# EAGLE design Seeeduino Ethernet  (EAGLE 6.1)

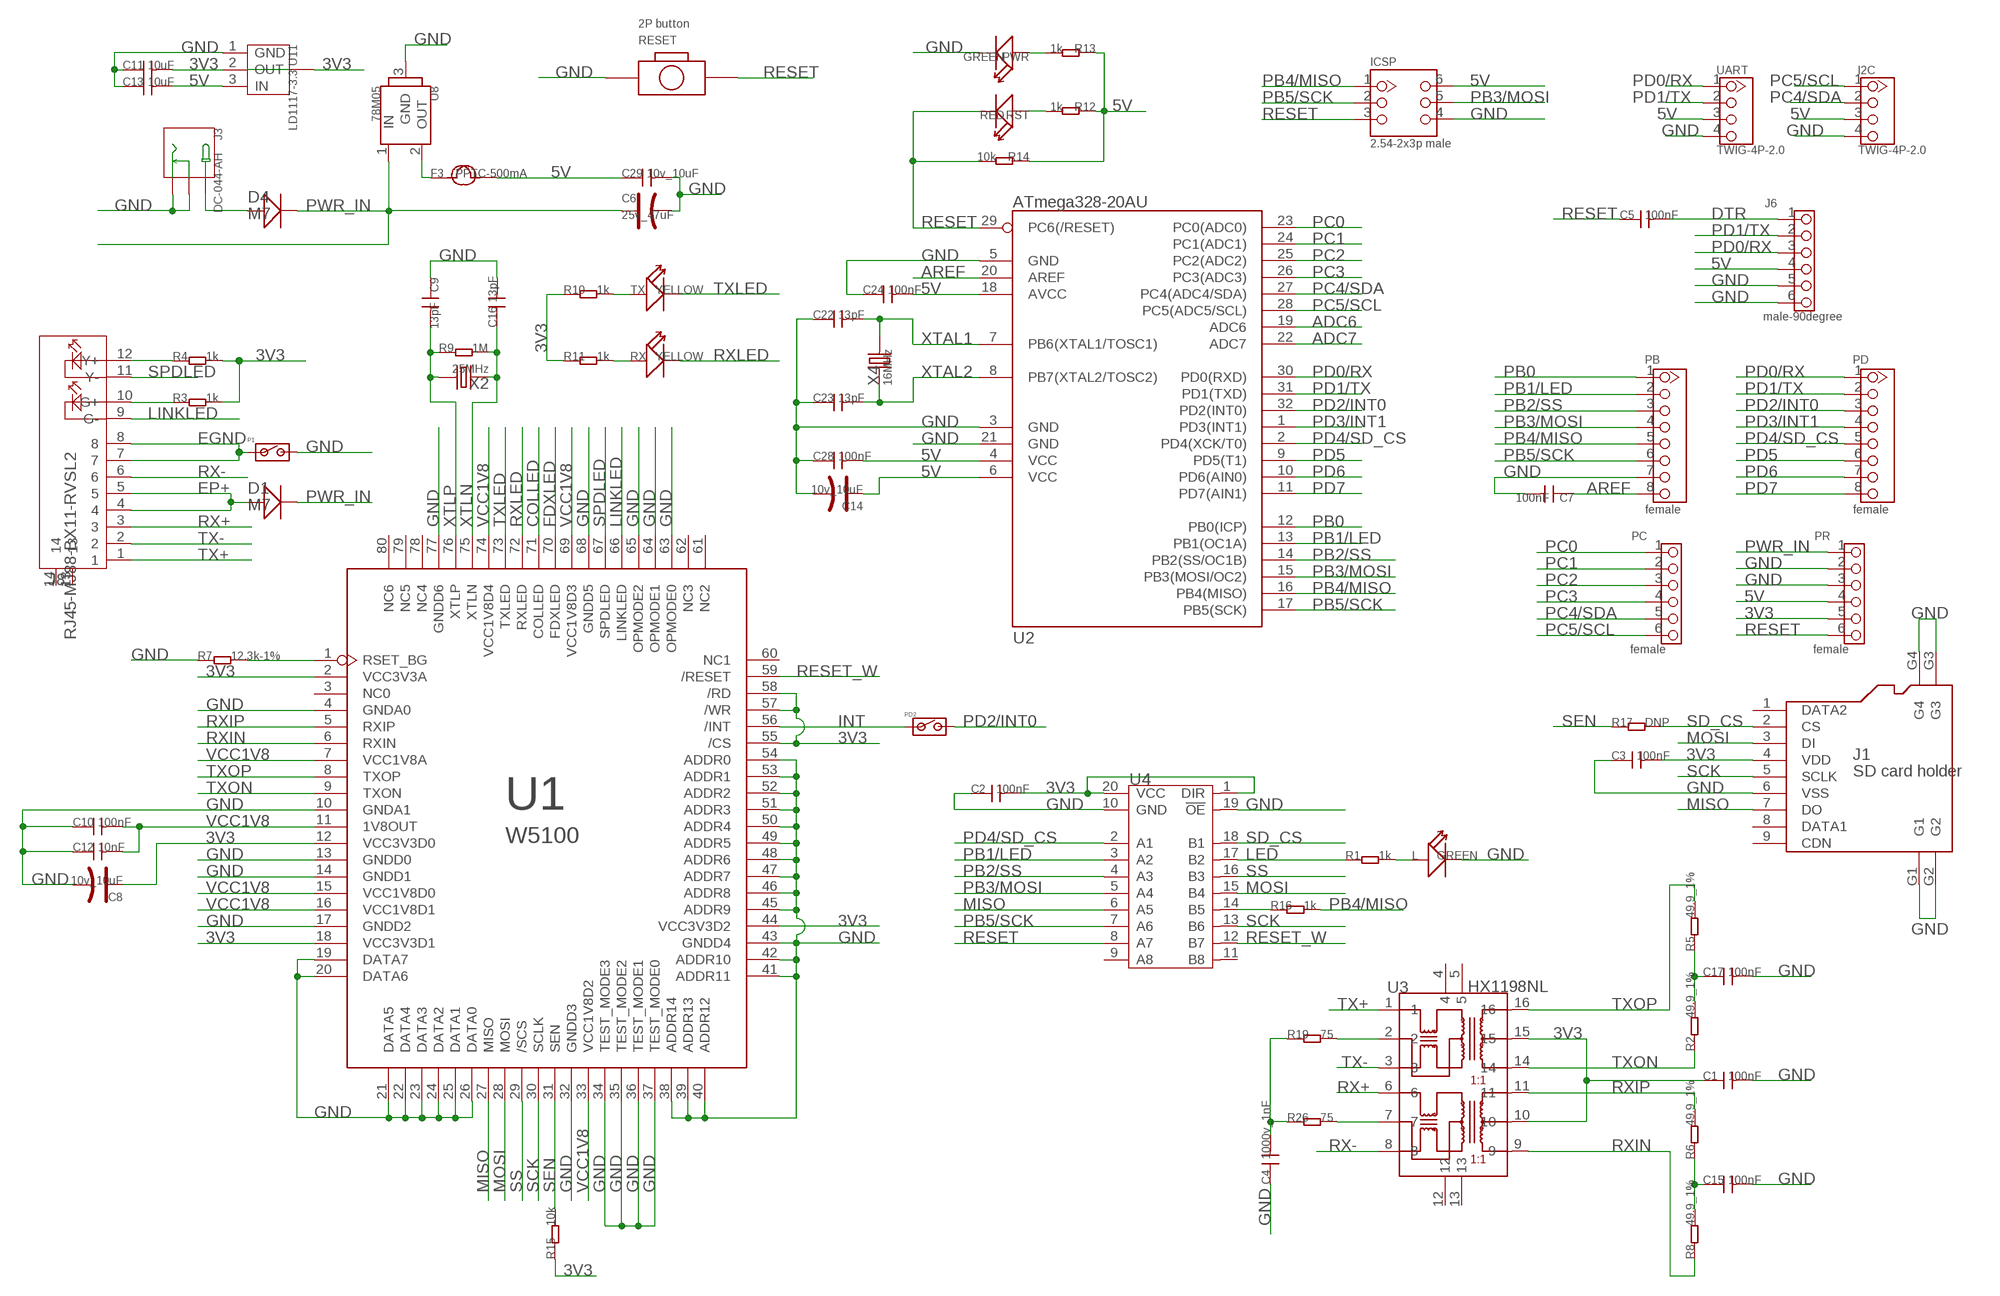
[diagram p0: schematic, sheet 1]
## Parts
C1  100nF  C-0603  [0603]
C2  100nF  C-0603  [0603]
C3  100nF  C-0603  [0603]
C4  1000v_1nF  C  [C1206]
C5  100nF  C-0603  [0603]
C6  25v_47uF  CAP-AVX-C  [AVX-C]
C7  100nF  C-0603  [0603]
C8  10v_10uF  CAP-AVX-A  [AVX-A]
C9  13pF  C-0603  [0603]
C10  100nF  C-0603  [0603]
C11  10uF  C-0805  [0805]
C12  10nF  C-0603  [0603]
C13  10uF  C-0805  [0805]
C14  10v_10uF  CAP-AVX-A  [AVX-A]
C15  100nF  C-0603  [0603]
C16  13pF  C-0603  [0603]
C17  100nF  C-0603  [0603]
C22  13pF  C-0603  [0603]
C23  13pF  C-0603  [0603]
C24  100nF  C-0603  [0603]
C28  100nF  C-0603  [0603]
C29  10v_10uF  C-0805  [0805]
D1  M7  D-SMA  [D2010]
D4  M7  D-SMA  [D2010]
F3  PPTC-500mA  FUSE  [1206]
I2C  TWIG-4P-2.0  TWIG-4P-2.0-2.0  [4P-2.0]
ICSP  2.54-2x3p male  HEADER-2X3P-2.54  [2X3P-2.54]
J1  SD card holder  HOLDER-MICROSD-9P  [9P-SMD-W/-RING]
J3  DC-044-AH  DC-044  [DC-404]
J6  male-90degree  HEADER-6P-65/35MIL  [6P-2.54-65/35MIL]
J8  RJ45-MJ88-BX11-RVSL2  [RJ45-MJ88-BX11-RVSL2]
L  GREEN  LED'0603'  [LED-0603]
P1  DNP  PAD-JUMPER-2P  [2P-SMD-1.78X1.27]
PB  female  HEADER-8P-2.54  [8P-2.54]
PC  female  HEADER-6P-65/35MIL  [6P-2.54-65/35MIL]
PD  female  HEADER-8P-2.54  [8P-2.54]
PD2  DNP  PAD-JUMPER-2P  [2P-SMD-1.78X1.27]
PR  female  HEADER-6P-65/35MIL  [6P-2.54-65/35MIL]
PWR  GREEN  LED'0603'  [LED-0603]
R1  1k  R-0603  [0603]
R2  49.9_1%  R-0603  [0603]
R3  1k  R-0603  [0603]
R4  1k  R-0603  [0603]
R5  49.9_1%  R-0603  [0603]
R6  49.9_1%  R-0603  [0603]
R7  12.3k-1%  R-0603  [0603]
R8  49.9_1%  R-0603  [0603]
R9  1M  R-0603  [0603]
R10  1k  R-0603  [0603]
R11  1k  R-0603  [0603]
R12  1k  R-0603  [0603]
R13  1k  R-0603  [0603]
R14  10k  R-0603  [0603]
R15  10k  R-0603  [0603]
R16  1k  R-0603  [0603]
R17  DNP  R-0603  [0603]
R19  75  R-0603  [0603]
R26  75  R-0603  [0603]
RESET  2P button  BOTTON-2P-90  [2P-7.62X3.56-90D]
RST  RED  LED'0603'  [LED-0603]
RX  YELLOW  LED'0603'  [LED-0603]
TX  YELLOW  LED'0603'  [LED-0603]
U1  W5100  [SQFP80]
U2  ATmega328-20AU  ATMEGA168  [TQFP32]
U3  HX1198NL  [SOIC16-9.53]
U4  74ACT245  [TSSOP20]
U8  78M05  78M05-TO252  [TO252]
U11  LD1117-3.3  LD1117SOT223  [SOT-223]
UART  TWIG-4P-2.0  TWIG-4P-2.0-2.0  [4P-2.0]
X2  25MHz  CRYSTAL-5032  [2P-SMD-5X3.2]
X4  16MHz  CRYSTAL-5032  [2P-SMD-5X3.2]

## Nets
3V3: C1.1 C2.2 C3.2 C8.+ C11.2 J1.4(VDD) PR.5 R3.2 R4.2 R10.1 R11.1 R15.1 U1.2(VCC3V3A) U1.12(VCC3V3D0) U1.18(VCC3V3D1) U1.44(VCC3V3D2) U1.55(/CS) U1.57(/WR) U1.58(/RD) U3.10 U3.15 U4.1(DIR) U4.20(VCC) U11.2(OUT) U11.TER(TAB)
5V [usbvcc]: C13.2 C14.+ C24.2 C28.2 C29.1 F3.2 I2C.3 ICSP.6 J6.4 PR.4 R12.1 R13.1 R14.1 U2.4(VCC) U2.6(VCC) U2.18(AVCC) U11.3(IN) UART.3
ADC6: U2.19(ADC6)
ADC7: U2.22(ADC7)
AREF: C7.1 PB.8 U2.20(AREF)
COLLED: U1.71(COLLED)
DTR: C5.2 J6.1
EGND [power]: J8.7 J8.8 P1.1
EP+: D1.+ J8.4 J8.5
FDXLED: U1.70(FDXLED)
GND [power]: C1.2 C2.1 C3.1 C4.1 C6.- C7.2 C8.- C9.1 C10.1 C11.1 C12.1 C13.1 C14.- C15.2 C16.2 C17.2 C22.1 C23.1 C24.1 C28.1 C29.2 I2C.4 ICSP.4 J1.6(VSS) J1.G1 J1.G2 J1.G3 J1.G4 J3.- J3.CDN J6.5 J6.6 L.- P1.2 PB.7 PR.2 PR.3 PWR.- R7.1 RESET.P$1 U1.4(GNDA0) U1.10(GNDA1) U1.13(GNDD0) U1.14(GNDD1) U1.17(GNDD2) U1.19(DATA7) U1.20(DATA6) U1.21(DATA5) U1.22(DATA4) U1.23(DATA3) U1.24(DATA2) U1.25(DATA1) U1.26(DATA0) U1.32(GNDD3) U1.34(TEST_MODE3) U1.35(TEST_MODE2) U1.36(TEST_MODE1) U1.37(TEST_MODE0) U1.38(ADDR14) U1.39(ADDR13) U1.40(ADDR12) U1.41(ADDR11) U1.42(ADDR10) U1.43(GNDD4) U1.45(ADDR9) U1.46(ADDR8) U1.47(ADDR7) U1.48(ADDR6) U1.49(ADDR5) U1.50(ADDR4) U1.51(ADDR3) U1.52(ADDR2) U1.53(ADDR1) U1.54(ADDR0) U1.63(OPMODE0) U1.64(OPMODE1) U1.65(OPMODE2) U1.68(GNDD5) U1.77(GNDD6) U2.3(GND) U2.5(GND) U2.21(GND) U4.10(GND) U4.19(!OE) U8.3(GND) U11.1(GND) UART.4
INT: PD2.1 U1.56(/INT)
LED: R1.1 U4.17(B2)
LINKLED: J8.9(G-) U1.66(LINKLED)
MISO: J1.7(DO) U1.27(MISO) U4.6(A5)
MOSI: J1.3(DI) U1.28(MOSI) U4.15(B4)
N$1: L.+ R1.2
N$2: J8.12(Y+) R4.1
N$3: PWR.+ R13.2
N$4: J8.10(G+) R3.1
N$5: D4.+ J3.+
N$6: R10.2 TX.+
N$7: R11.2 RX.+
N$8: R26.2 U3.7
N$9: R19.2 U3.2
N$10: C4.2 R19.1 R26.1
N$11: F3.1 U8.2(OUT)
N$12: R16.1 U4.14(B5)
N$13: C15.1 R6.1 R8.2
N$14: C17.1 R2.2 R5.1
N$17: R12.2 RST.+
N$38: R7.2 U1.1(RSET_BG)
PB0: PB.1 U2.12(PB0(ICP))
PB1/LED: PB.2 U2.13(PB1(OC1A)) U4.3(A2)
PB2/SS: PB.3 U2.14(PB2(SS/OC1B)) U4.4(A3)
PB3/MOSI: ICSP.5 PB.4 U2.15(PB3(MOSI/OC2)) U4.5(A4)
PB4/MISO: ICSP.1 PB.5 R16.2 U2.16(PB4(MISO))
PB5/SCK: ICSP.2 PB.6 U2.17(PB5(SCK)) U4.7(A6)
PC0: PC.1 U2.23(PC0(ADC0))
PC1: PC.2 U2.24(PC1(ADC1))
PC2: PC.3 U2.25(PC2(ADC2))
PC3: PC.4 U2.26(PC3(ADC3))
PC4/SDA: I2C.2 PC.5 U2.27(PC4(ADC4/SDA))
PC5/SCL: I2C.1 PC.6 U2.28(PC5(ADC5/SCL))
PD0/RX: J6.3 PD.1 U2.30(PD0(RXD)) UART.1
PD1/TX: J6.2 PD.2 U2.31(PD1(TXD)) UART.2
PD2/INT0: PD2.2 PD.3 U2.32(PD2(INT0))
PD3/INT1: PD.4 U2.1(PD3(INT1))
PD4/SD_CS: PD.5 U2.2(PD4(XCK/T0)) U4.2(A1)
PD5: PD.6 U2.9(PD5(T1))
PD6: PD.7 U2.10(PD6(AIN0))
PD7: PD.8 U2.11(PD7(AIN1))
PWR_IN: C6.+ D1.- D4.- PR.1 U8.1(IN)
RESET: C5.1 ICSP.3 PR.6 R14.2 RESET.P$2 RST.- U2.29(PC6(/RESET)) U4.8(A7)
RESET_W: U1.59(/RESET) U4.12(B7)
RX+: J8.3 U3.6
RX-: J8.6 U3.8
RXIN: R8.1 U1.6(RXIN) U3.9
RXIP: R6.2 U1.5(RXIP) U3.11
RXLED: RX.- U1.72(RXLED)
SCK: J1.5(SCLK) U1.30(SCLK) U4.13(B6)
SD_CS: J1.2(CS) R17.2 U4.18(B1)
SEN: R15.2 R17.1 U1.31(SEN)
SPDLED: J8.11(Y-) U1.67(SPDLED)
SS: U1.29(/SCS) U4.16(B3)
TX+: J8.1 U3.1
TX-: J8.2 U3.3
TXLED: TX.- U1.73(TXLED)
TXON: R2.1 U1.9(TXON) U3.14
TXOP: R5.2 U1.8(TXOP) U3.16
VCC1V8: C10.2 C12.2 U1.7(VCC1V8A) U1.11(1V8OUT) U1.15(VCC1V8D0) U1.16(VCC1V8D1) U1.33(VCC1V8D2) U1.69(VCC1V8D3) U1.74(VCC1V8D4)
XTAL1: C22.2 U2.7(PB6(XTAL1/TOSC1)) X4.2
XTAL2: C23.2 U2.8(PB7(XTAL2/TOSC2)) X4.1
XTLN: C16.1 R9.2 U1.75(XTLN) X2.1
XTLP: C9.2 R9.1 U1.76(XTLP) X2.2
Unconnected: J1.1(DATA2) J1.8(DATA1) J1.9(CDN) J8.13 J8.14 U1.3(NC0) U1.60(NC1) U1.61(NC2) U1.62(NC3) U1.78(NC4) U1.79(NC5) U1.80(NC6) U3.4 U3.5 U3.12 U3.13 U4.9(A8) U4.11(B8)

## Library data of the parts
C1-C5 C7 C9-C13 C15-C17 C22-C24 C28 C29 = Discrete:C*: Ceramic Capacitors
C6 C8 C14 = Discrete:CAP*: Electrolytic Capacitors,Tantalum Capacitors and Super Capacitors
D1 D4 = Discrete:D*
F3 = Discrete:FUSE
I2C UART = Connector:TWIG-4P-2.0
ICSP = Connector:HEADER-2X3P
J1 = Connector:HOLDER-MICROSD-9P
J3 = For_Test_Albert:DC-044
J6 PC PR = Connector:HEADER-6P
J8 = Connector:RJ45-MJ88-BX11-RVSL2: Modular Jack 8P8C,R/A,With LED
L PWR RST RX TX = Discrete:LED*
P1 PD2 = Discrete:PAD-JUMPER-2P
PB PD = Connector:HEADER-8P
R1-R17 R19 R26 = Discrete:R*
RESET = Discrete:BOTTON-2P
U1 = ICs_v54:W5100
U2 = IC:ATMEGA168: MICROCONTROLLER
U3 = IC:HX1198NL: 10/100BASE-T Single Port Surface Mount Magnetics With Various Turns Ratios
U4 = IC:74ACT245: Octal Bus Transceiver With 3 State Outputs (NON INVERTED) http://www.datasheetcatalog.org/datasheet/stmicroelectronics/4823.pdf
U8 = IC:78M05: 0.5A Three Terminal Positive Voltage Regulators http://pdf1.alldatasheet.com/datasheet-pdf/view/31368/TOSHIBA/78M05/+21_79UPLRhpDDdCDytD+/datasheet.pdf
U11 = IC:LD1117: Low Drop Fixed And Adjustable Positive Voltage Regulators http://www.datasheetcatalog.org/datasheet/SGSThomsonMicroelectronics/mXuqtqv.pdf
X2 X4 = Discrete:CRYSTAL*: CRYSTAL

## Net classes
0 default: width 0.203 mm, drill 0.305 mm, clearance 0.152 mm
3 usbvcc: width 0.203 mm, drill 0.305 mm, clearance 0.203 mm

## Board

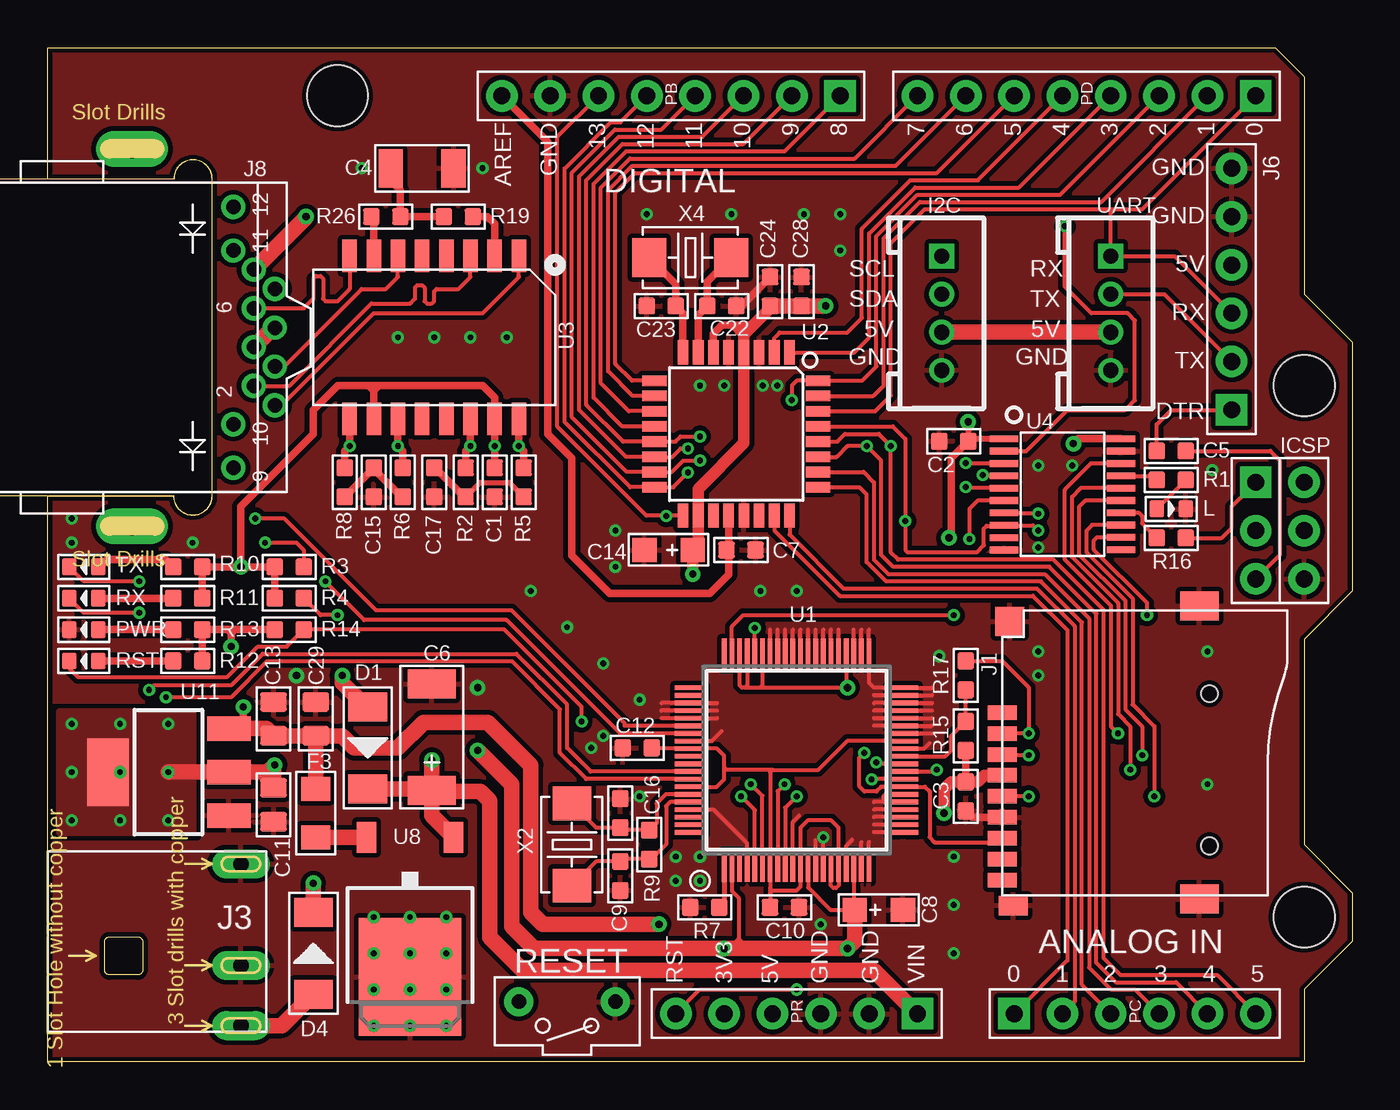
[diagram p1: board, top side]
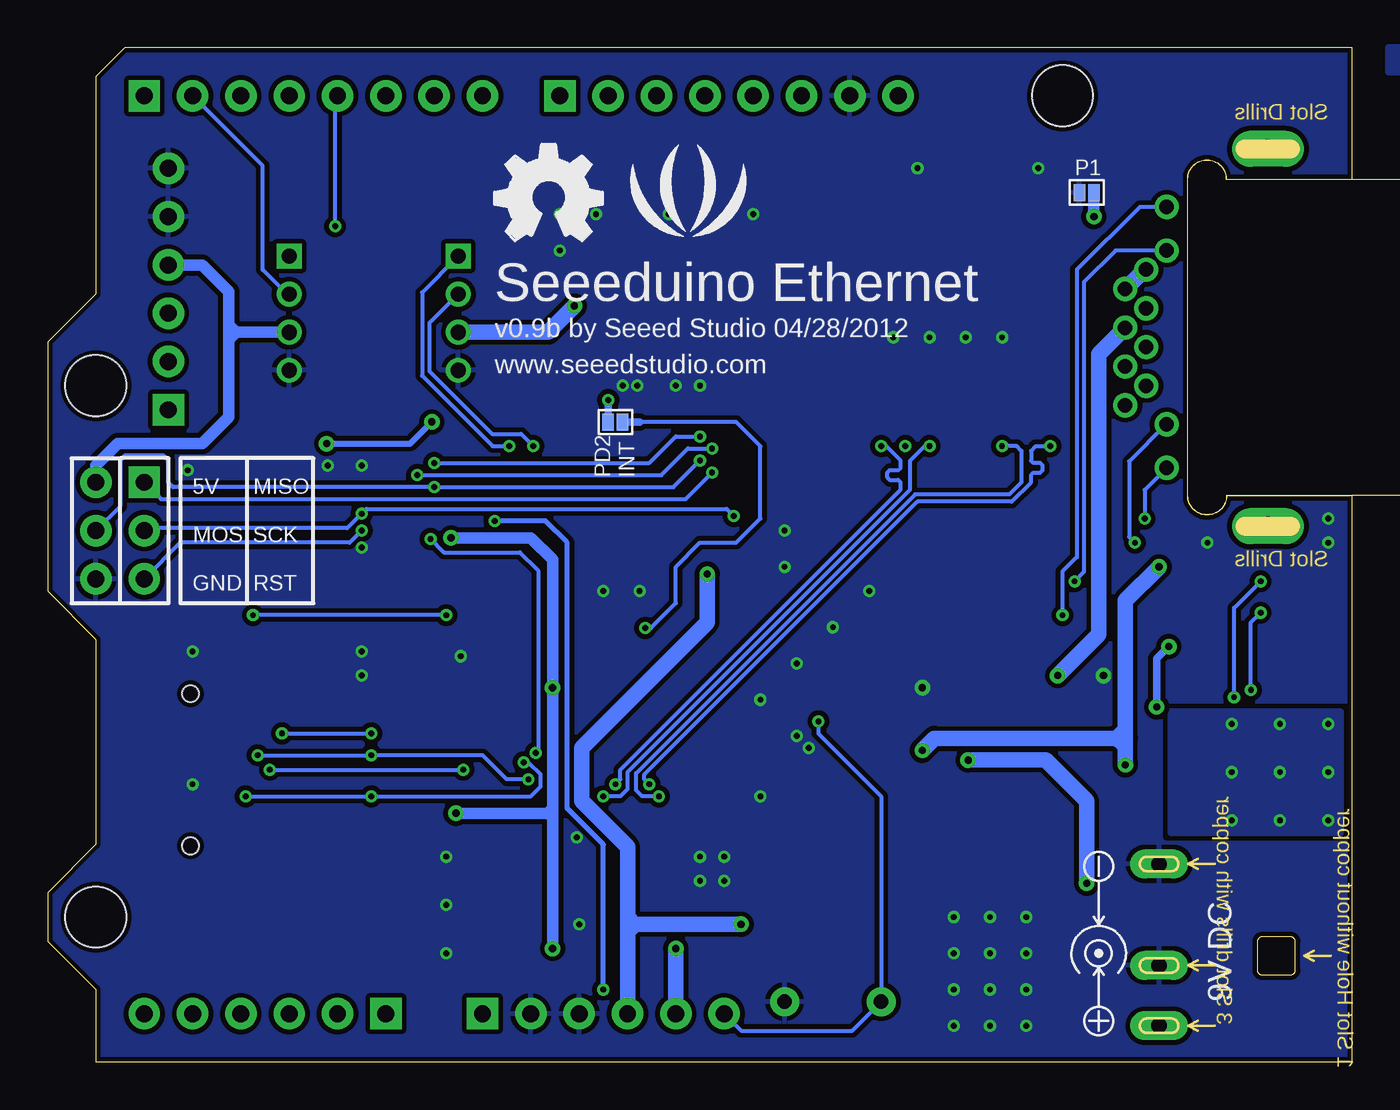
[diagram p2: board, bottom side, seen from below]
Size 68.58 x 53.34 mm. Coordinates in mm from the lower left corner, seen from the top.
Outline: 0,53.34 64.52,53.34 66.04,51.82 66.04,40.39 68.58,37.85 68.58,24.77 66.04,22.23 66.04,11.43 68.58,8.89 68.58,6.35 66.04,3.81 66.04,0 0,0 0,29.77 6.61,29.77 6.61,29.76 arc90 7.61,28.76 7.66,28.76 arc90 8.66,29.76 8.66,46.44 arc90 7.66,47.44 7.63,47.44 arc89 6.63,46.45 6.63,46.43 0,46.43 0,53.34
Copper layers (1*16): Top 0.035mm / dielectric 1.5mm / Bottom 0.035mm
Design rules: minimum track width 5mil, minimum drill 10mil, track to track 6mil, track to pad 6mil, pad to pad 6mil, via to via 6mil, smd to smd 6mil, copper to edge 10mil, drill to drill 10mil, minimum pad ring 10mil, minimum via ring 6mil, stop-mask expansion 2mil, vias tented up to drill 100mil, thermal gap 10mil
Holes 3.2 mm at 66.04,35.56 66.04,7.62 15.24,50.8
tRestrict: area 33.1,12 to 34.4,19.8; area 35.5,20.8 to 43.3,22.1; area 35.5,9.7 to 43.3,10.9; area 44.3,12 to 45.6,19.8

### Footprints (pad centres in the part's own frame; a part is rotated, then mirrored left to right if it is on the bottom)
0603 = smd 0.889 x 0.889: 1 -0.762,0; 2 0.762,0
C1206 = smd 1.27 x 2.032: 1 -1.651,0; 2 1.651,0
AVX-C = smd 1.524 x 2.54: + -2.794,0; - 2.794,0
AVX-A = smd 1.27 x 1.27: + -1.27,0; - 1.27,0
0805 = smd 1.016 x 1.397: 1 -0.889,0; 2 0.889,0
D2010 = smd 1.524 x 2.032: + -2.159,0; - 2.159,0
1206 = smd 1.27 x 1.524: 1 -1.27,0; 2 1.27,0
4P-2.0 = drill 0.8 pad 1.27 square: 1 -3,0 | drill 0.8 pad 1.27: 2 -1,0; 3 1,0; 4 3,0
2X3P-2.54 = drill 0.889 pad 1.651 square: 1 -1.27,2.54 | drill 0.889 pad 1.651: 2 -1.27,0; 3 -1.27,-2.54; 4 1.27,-2.54; 5 1.27,0; 6 1.27,2.54
9P-SMD-W/-RING = smd 1.524 x 0.762: 1 0,4.4; 2 0,3.3; 3 0,2.2; 4 0,1.1; 5 0,0; 6 0,-1.1; 7 0,-2.2; 8 0,-3.3; 9 0,-4.4 | smd 1.524 x 1.016: G1 0.6,-5.746 | smd 2.032 x 1.524: G2 10.373,-5.4; G3 10.373,10 | smd 1.524 x 1.524: G4 0.392,9.181 | hole 0.889: 10.9,-2.6; 10.9,5.4
DC-404 = drill 0.813 pad 1.524 long: + 3.175,10.16; - -5.334,10.16; CDN 0,10.16
6P-2.54-65/35MIL = drill 0.889 pad 1.651 square: 1 0,6.35 | drill 0.889 pad 1.651: 2 0,3.81; 3 0,1.27; 4 0,-1.27; 5 0,-3.81; 6 0,-6.35
RJ45-MJ88-BX11-RVSL2 = drill 0.762 pad 1.27: 1 3.57,7.5; 2 2.55,6.4; 3 1.53,7.5; 4 0.51,6.4; 5 -0.51,7.5; 6 -1.53,6.4; 7 -2.55,7.5; 8 -3.57,6.4; 9 6.86,5.32; 10 4.57,5.32; 11 -4.57,5.32; 12 -6.86,5.32 | drill 1 pad 1.9 long: 13 -9.92,0; 14 9.92,0
LED-0603 = smd 0.762 x 0.889: + -0.762,0; - 0.762,0
2P-SMD-1.78X1.27 = smd 0.889 x 0.61: 1 0,0.381; 2 0,-0.381
8P-2.54 = drill 0.889 pad 1.651 square: 1 0,8.89 | drill 0.889 pad 1.651: 2 0,6.35; 3 0,3.81; 4 0,1.27; 5 0,-1.27; 6 0,-3.81; 7 0,-6.35; 8 0,-8.89
2P-7.62X3.56-90D = drill 0.762 pad 1.524: P$1 0,2.54; P$2 0,-2.54
SQFP80 = smd 1.6 x 0.25: 1 -5.6,3.8; 2 -5.6,3.4; 3 -5.6,3; 4 -5.6,2.6; 5 -5.6,2.2; 6 -5.6,1.8; 7 -5.6,1.4; 8 -5.6,1; 9 -5.6,0.6; 10 -5.6,0.2; 11 -5.6,-0.2; 12 -5.6,-0.6; 13 -5.6,-1; 14 -5.6,-1.4; 15 -5.6,-1.8; 16 -5.6,-2.2; 17 -5.6,-2.6; 18 -5.6,-3; 19 -5.6,-3.4; 20 -5.6,-3.8; 41 5.6,-3.8; 42 5.6,-3.4; 43 5.6,-3; 44 5.6,-2.6; 45 5.6,-2.2; 46 5.6,-1.8; 47 5.6,-1.4; 48 5.6,-1; 49 5.6,-0.6; 50 5.6,-0.2; 51 5.6,0.2; 52 5.6,0.6; 53 5.6,1; 54 5.6,1.4; 55 5.6,1.8; 56 5.6,2.2; 57 5.6,2.6; 58 5.6,3; 59 5.6,3.4; 60 5.6,3.8 | smd 0.25 x 1.6: 21 -3.8,-5.6; 22 -3.4,-5.6; 23 -3,-5.6; 24 -2.6,-5.6; 25 -2.2,-5.6; 26 -1.8,-5.6; 27 -1.4,-5.6; 28 -1,-5.6; 29 -0.6,-5.6; 30 -0.2,-5.6; 31 0.2,-5.6; 32 0.6,-5.6; 33 1,-5.6; 34 1.4,-5.6; 35 1.8,-5.6; 36 2.2,-5.6; 37 2.6,-5.6; 38 3,-5.6; 39 3.4,-5.6; 40 3.8,-5.6; 61 3.8,5.6; 62 3.4,5.6; 63 3,5.6; 64 2.6,5.6; 65 2.2,5.6; 66 1.8,5.6; 67 1.4,5.6; 68 1,5.6; 69 0.6,5.6; 70 0.2,5.6; 71 -0.2,5.6; 72 -0.6,5.6; 73 -1,5.6; 74 -1.4,5.6; 75 -1.8,5.6; 76 -2.2,5.6; 77 -2.6,5.6; 78 -3,5.6; 79 -3.4,5.6; 80 -3.8,5.6
TQFP32 = smd 1.27 x 0.559: 1 -4.293,2.8; 2 -4.293,2; 3 -4.293,1.2; 4 -4.293,0.4; 5 -4.293,-0.4; 6 -4.293,-1.2; 7 -4.293,-2; 8 -4.293,-2.8; 17 4.293,-2.8; 18 4.293,-2; 19 4.293,-1.2; 20 4.293,-0.4; 21 4.293,0.4; 22 4.293,1.2; 23 4.293,2; 24 4.293,2.8 | smd 0.559 x 1.27: 9 -2.8,-4.293; 10 -2,-4.293; 11 -1.2,-4.293; 12 -0.4,-4.293; 13 0.4,-4.293; 14 1.2,-4.293; 15 2,-4.293; 16 2.8,-4.293; 25 2.8,4.293; 26 2,4.293; 27 1.2,4.293; 28 0.4,4.293; 29 -0.4,4.293; 30 -1.2,4.293; 31 -2,4.293; 32 -2.8,4.293
SOIC16-9.53 = smd 0.762 x 1.714: 1 -4.445,-4.286; 2 -3.175,-4.286; 3 -1.905,-4.286; 4 -0.635,-4.286; 5 0.635,-4.286; 6 1.905,-4.286; 7 3.175,-4.286; 8 4.445,-4.286; 9 4.445,4.286; 10 3.175,4.286; 11 1.905,4.286; 12 0.635,4.286; 13 -0.635,4.286; 14 -1.905,4.286; 15 -3.175,4.286; 16 -4.445,4.286
TSSOP20 = smd 0.35 x 1.5: 1 -2.925,-3.065; 2 -2.275,-3.065; 3 -1.625,-3.065; 4 -0.975,-3.065; 5 -0.325,-3.065; 6 0.325,-3.065; 7 0.975,-3.065; 8 1.625,-3.065; 9 2.275,-3.065; 10 2.925,-3.065; 11 2.91,3.065; 12 2.26,3.065; 13 1.61,3.065; 14 0.96,3.065; 15 0.325,3.065; 16 -0.325,3.065; 17 -0.975,3.065; 18 -1.625,3.065; 19 -2.275,3.065; 20 -2.925,3.065
TO252 = smd 1.016 x 1.651: 1 -2.286,-4.826; 2 2.286,-4.826 | smd 5.4 x 6.2: 3 0,2.5
SOT-223 = smd 1.27 x 2.286: 1 -2.286,-3.175; 2 0,-3.175; 3 2.286,-3.175 | smd 3.556 x 2.159: TER 0,3.175
2P-SMD-5X3.2 = smd 1.778 x 2.032: 1 -2.159,0; 2 2.159,0

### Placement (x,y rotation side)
C1  23.5,30.48 270 top
C2  47.62,32.64 0 top
C3  48.26,13.97 90 top
C4  19.68,46.99 180 top
C5  59.05,32.13 180 top
C6  20.19,17.08 90 top
C7  36.45,26.92 0 top
C8  43.69,8 0 top
C9  30.1,9.78 90 top
C10  38.73,8.13 180 top
C11  11.87,13.53 90 top
C12  30.99,16.51 0 top
C13  11.87,18.03 270 top
C14  32.64,26.92 180 top
C15  17.14,30.48 270 top
C16  30.1,13.08 90 top
C17  20.32,30.48 270 top
C22  35.43,39.75 180 top
C23  32.26,39.75 0 top
C24  37.97,40.51 270 top
C28  39.62,40.51 270 top
C29  14.1,18.03 90 top
D1  16.83,16.51 270 top
D4  13.97,5.71 90 top
F3  14.1,13.08 90 top
I2C  46.99,39.37 270 top
ICSP  64.77,27.94 0 top
J1  50.16,13.97 0 top
J3  0,5.08 270 top
J6  62.23,40.64 180 top
J8  4.45,38.1 270 top
L  59.05,29.08 0 top
P1  13.97,45.72 270 bottom
PB  32.77,50.8 270 top
PC  57.15,2.54 90 top
PD  54.61,50.8 270 top
PD2  38.73,33.66 270 bottom
PR  39.37,2.54 270 top
PWR  1.91,22.73 180 top
R1  59.05,30.61 0 top
R2  21.97,30.48 270 top
R3  12.7,26.04 180 top
R4  12.7,24.38 180 top
R5  25.02,30.48 90 top
R6  18.67,30.48 90 top
R7  34.54,8.13 0 top
R8  15.62,30.48 270 top
R9  31.62,11.43 90 top
R10  7.37,26.04 180 top
R11  7.37,24.38 180 top
R12  7.37,21.08 180 top
R13  7.37,22.73 180 top
R14  12.7,22.73 0 top
R15  48.26,17.14 90 top
R16  59.05,27.56 0 top
R17  48.26,20.32 90 top
R19  21.59,44.45 0 top
R26  17.78,44.45 180 top
RESET  27.3,3.17 270 top
RST  1.91,21.08 180 top
RX  1.91,24.38 180 top
TX  1.91,26.04 180 top
U1  39.37,15.88 90 top
U2  36.2,33.02 270 top
U3  20.32,38.1 180 top
U4  53.34,29.84 270 top
U8  19.05,6.99 180 top
U11  6.35,15.24 90 top
U$1  [OSHW_FILLX200_NOTEXT]  45.09,43.18 0 bottom
U$2  [LOGO_SILK]  34.92,45.09 0 bottom
UART  55.88,39.37 270 top
X2  27.56,11.43 270 top
X4  33.78,42.29 0 top

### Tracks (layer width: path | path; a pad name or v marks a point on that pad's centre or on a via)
3V3  (via drill 0.3 pad 0.64, 0.38 pad 0.81)
  Top 0.203: U4.1 | U1.2 35.97,8.99 36.32,8.64 36.32,6.48 | U1.12 39.97,9.18 41.15,8 C8.+ 42.37,8.05 U1.18 | U1.44 41.97,19.75 v42.04,19.68 37.7,19.68 | U1.55 37.57,19.81 | 37.57,19.81 37.7,19.68 | U1.57 36.77,19.81 | 36.77,19.81 36.64,19.68 | 36.64,19.68 36.5,19.68 36.37,19.81 U1.58 | 36.77,19.81 36.9,19.68 | 37.57,19.81 37.44,19.68 | 36.64,19.68 37.7,19.68 | 36.32,6.48 35.81,5.97 | 36.32,6.48 36.83,5.97
  Top 0.305: v48.39,33.66 C2.2 48.51,32.77 U4.1
  Top 0.406: R11.1 8.13,25.91 8.26,26.04 | R3.2 12.06,26.04 | R4.2 R3.2 | R10.1 8.26,26.04 | v47.37,27.56 47.5,27.56 47.5,31.75 C2.2 | U4.20 54.17,32.77 v53.91,32.51 | C1.1 v23.5,32.38 U3.15 23.5,34.92 22.86,35.56 17.4,35.56 | 8.26,26.04 v10.16,26.04 | R3.2 v10.16,26.04 | v10.16,26.04 10.16,29.21 13.97,33.02 13.97,34.29 15.24,35.56 16.89,35.56 | 16.89,35.56 17.4,35.56 | U3.10 17.14,35.31 | 17.14,35.31 16.89,35.56 | 17.4,35.56 17.14,35.31 | C3.2 R15.1
  Top 0.61: v47.12,13.08 47.12,14.35 47.5,14.73 C3.2 48.9,14.73 49.23,15.07 J1.4
  Top 0.813: v6.35,15.24 U11.2 11.56,15.24 v11.94,15.62 11.87,15.56 C11.2 | v22.61,16.38 24.38,14.61 24.38,7.14 25.55,5.97 v35.56,5.97 35.81,5.97 36.83,5.97 v42.04,5.97 42.42,6.35 C8.+ 42.42,8.13
  Bottom 0.305: v53.91,32.51 49.53,32.51 v48.39,33.66
  Bottom 0.61: v47.37,27.56 43.18,27.56 42.04,26.42 v42.04,19.68 42.04,13.34 | v42.04,5.97 42.04,12.83 | 42.04,12.83 42.04,13.08 | 42.04,13.08 42.04,13.34 | v47.12,13.08 42.29,13.08 | 42.29,13.08 42.04,13.08 | 42.29,13.08 42.04,13.34 | 42.29,13.08 42.04,12.83
  Bottom 0.813: 11.94,15.75 v11.94,15.62 11.94,17.02 | 11.94,17.02 11.94,24.26 v10.16,26.04 | v22.61,16.38 21.97,17.02 12.38,17.02 | 12.38,17.02 11.94,17.02 | 12.38,17.02 12,17.4 | 12.38,17.02 12,16.64 | v35.56,5.97 PR.5
  other vias: 1.27,17.78 1.27,15.24 1.27,12.7 3.81,17.78 6.35,17.78 6.35,12.7 3.81,12.7 3.81,15.24
  pour Top (isolate 0.254, no thermals): 0.64,18.41 7.62,18.41 7.62,12.06 0.64,12.06
  pour Bottom (isolate 0.254, no thermals): 0.64,18.41 9.53,18.41 9.53,12.06 0.64,12.06
5V  (via drill 0.38 pad 0.81)
  Top 0.406: U2.6 34.99,38.3 35.43,38.73 36.01,38.73 | 36.01,38.73 36.32,38.73 | 36.32,38.73 36.58,38.73 | 36.58,38.73 36.96,38.73 | 36.96,38.73 C24.2 | 36.59,38.37 36.59,38.25 36.49,38.25 36.01,38.73 | 36.59,38.46 36.59,38.72 36.58,38.73 | 36.59,38.37 36.59,38.46 | 36.59,38.46 36.32,38.73 | 36.59,38.37 36.96,38.73 | U2.18 34.2,27.21 C14.+ | R12.1 R13.1 9.46,22.73 | R14.1 9.84,22.73 | 9.84,22.73 9.65,22.73 | 9.65,22.73 9.46,22.73 | U11.3 10.16,17.53 10.29,17.4 v10.29,18.67 | v9.65,21.84 9.65,22.54 | 9.65,22.73 9.65,22.54 | 9.65,22.54 9.46,22.73 | 9.65,22.54 9.84,22.73
  Top 0.61: 33.78,26.92 34.2,27.34 U2.18 34.2,30.13 36.59,32.53 U2.4 36.59,38.25 38.1,39.75 | v33.91,25.65 C14.+
  Top 0.813: I2C.3 UART.3 | v40.89,39.75 C28.2 38.1,39.75 C24.2 | U11.3 11.49,17.53 C13.2 C29.1 | F3.2 C29.1 | C29.1 15.49,17.14 16.13,16.51 18.41,16.51 19.77,17.87 23.13,17.87 25.4,15.6 25.4,7.87 26.04,7.24 v32.13,7.24
  Bottom 0.406: v10.29,18.67 10.29,21.21 v9.65,21.84
  Bottom 0.61: J6.4 60.45,41.91 59.05,40.51 59.05,38.73 | 59.05,38.73 59.05,38.35 | 59.05,38.35 59.05,37.97 | ICSP.6 66.04,31.37 64.89,32.51 60.45,32.51 59.05,33.91 59.05,37.97 | UART.3 58.66,38.37 | 58.69,38.37 59.04,38.37 59.05,38.35 | 58.66,38.37 58.69,38.37 | 58.69,38.37 59.05,38.73 | 58.66,38.37 59.05,37.97
  Bottom 0.813: I2C.3 42.27,38.37 v40.89,39.75 | PR.4 38.1,6.86 | 38.1,6.86 38.1,7.11 | 38.1,7.11 38.1,7.62 | 38.1,7.62 38.1,11.3 40.51,13.72 40.51,16.51 33.91,23.11 v33.91,25.65 | v32.13,7.24 37.72,7.24 | 37.72,7.24 37.97,7.24 38.1,7.11 | 37.72,7.24 38.1,7.62 | 37.72,7.24 38.1,6.86
AREF
  Top 0.406: PB.8 26.29,48.39 26.29,33.02 27.56,31.75 27.56,26.63 29.55,24.64 34.8,24.64 35.8,25.64 35.8,26.82 C7.1 35.8,27.03 U2.20
DTR
  Top 0.203: C5.2 58.29,33.53 59.05,34.29 J6.1
EGND  (via drill 0.38 pad 0.81)
  Top 0.813: J8.8 13.59,44.41 v13.59,44.45
  Bottom 0.61: P1.1 v13.59,44.45
  Bottom 0.813: J8.7 10.93,41.67 J8.8
EP+  (via drill 0.38 pad 0.81)
  Top 0.813: J8.5 11.87,38.61 J8.4 | v15.49,20.32 15.49,19.94 16.76,18.67 D1.+ 17.02,18.67
  Bottom 0.813: J8.5 13.34,37.22 13.34,22.48 v15.49,20.32
GND  (via drill 0.3 pad 0.64, 0.38 pad 0.81)
  Top 0.203: 33.78,18.86 U1.63 | 43.43,12.47 U1.22 43.53,12.47 | U1.54 37.97,22.73 | U1.53 38.37,22.73 | U1.52 38.77,22.73 | U1.51 39.17,22.73 | U1.50 39.57,22.73 | U1.48 40.37,22.73 | U1.43 42.37,22.73 | U1.45 41.57,22.73 | U1.46 41.17,22.73 | U1.47 40.77,22.73 | U1.42 42.77,22.73 | 43.17,22.73 U1.41 43.17,19.95 43.44,19.68 U1.40 46.48,19.68 | U1.49 39.97,22.73 | 43.43,19.27 U1.39 46.48,19.27 | 43.43,18.88 U1.38 46.48,18.88 | 43.43,18.48 U1.37 46.48,18.48 | 43.43,18.07 U1.36 46.48,18.07 | 43.43,17.68 U1.35 46.48,17.68 | U1.34 46.48,17.27 | U1.32 46.07,16.48 46.35,16.76 | U1.26 44.05,14.07 43.94,13.97 43.94,13.72 43.98,13.68 U1.25 43.43,13.68 | U1.24 43.43,13.28 | U1.23 43.43,12.88 | U1.21 43.43,12.07 | U1.19 42.77,11.56 | U1.20 43.17,11.56 | U1.17 41.97,11.36 42.29,11.68 | U1.4 36.77,11.49 34.98,13.28 U1.77 | U1.10 39.17,12.63 39.5,12.95 | U1.63 32.26,18.88 | 32.26,18.48 U1.64 35.18,18.48 | 32.26,18.07 U1.65 35.18,18.07 | U1.63 35.18,18.88 | U1.68 34.91,16.88 35.43,17.4 | U1.13 40.37,11.67 | U1.14 40.77,11.69
  Top 0.406: J1.6 48.6,12.87 C3.1 | C22.1 36.45,39.75 C24.1
  other vias: 53.85,31.37 13.08,20.32 17.14,1.91 19.05,1.91 20.95,1.91 20.95,3.81 19.05,3.81 17.14,3.81 17.14,5.71 17.14,7.62 19.05,7.62 20.95,7.62 20.95,5.71 19.05,5.71 22.61,19.68 34.29,35.56 35.56,35.56 37.59,35.56 38.35,35.56 31.5,44.58 35.94,44.58 39.75,44.58 41.66,42.67 41.66,44.58 52.07,31.37 52.07,27.05 46.86,21.34 47.62,8.26 31.11,13.97 33.02,9.53 47.62,10.79 47.62,5.71 52.07,21.59 60.96,21.59 60.96,14.61 16.51,46.99 22.86,46.99 61.21,31.11 40.64,7.24 29.84,27.94 25.4,24.77 31.11,19.05 1.27,28.57 1.27,27.3 7.62,27.3 29.21,17.14 28.57,16.51 29.84,26.04 40.77,11.81 52.07,20.32 37.47,24.77 39.37,24.77 33.02,10.79 34.29,10.79 34.29,9.53 29.21,20.95 27.3,22.86 20.32,38.1 22.23,38.1 24.13,38.1 18.41,38.1
  pour Bottom: -3.17,53.34 -1.91,53.34 -1.91,52.07 -3.17,52.07
  pour Top (isolate 0.254, rank 6): 0,53.98 69.22,53.98 69.22,0 0,0
  pour Bottom (isolate 0.254, rank 6): 0,53.98 69.22,53.98 69.22,0 0,0
INT  (via drill 0.3 pad 0.64)
  Top 0.203: U1.56 v37.17,22.82
  Bottom 0.203: v37.17,22.82 36.87,22.82 35.56,24.13 35.56,26.04 34.29,27.3 32.38,27.3 31.11,28.57 31.11,32.38 32.38,33.66 37.47,33.66
  Bottom 0.406: 37.47,33.66 PD2.1
LED
  Top 0.203: U4.17 58.08,30.82 R1.1
LINKLED  (via drill 0.3 pad 0.64)
  Top 0.203: U1.66 30.33,17.68 30.33,17.8 24.38,23.75 17.27,23.75 12.45,28.57 v10.92,28.57
  Bottom 0.203: J8.9 10.92,30.08 v10.92,28.57
MISO  (via drill 0.3 pad 0.64)
  Top 0.203: 50.12,11.77 49.91,11.56 46.61,11.56 46.35,11.81 46.35,14.22 46.1,14.47 U1.27 43.81,14.47 43.56,14.22 42.93,14.22 42.67,14.48 42.67,16 v42.93,16.26 | 50.12,11.77 50.16,11.81 | 50.25,11.68 J1.7 50.12,11.77 | U4.6 48.89,29.52 48.45,29.08 v48.45,27.5
  Bottom 0.203: v48.45,27.5 47.75,26.8 43.75,26.8 42.8,25.84 42.8,16.38 v42.93,16.26
MOSI  (via drill 0.3 pad 0.64)
  Top 0.203: v51.56,16.13 50.12,16.13 J1.3 | U1.28 43.32,14.88 v43.31,14.86 | U4.15 54.54,29.52 54.23,29.21 54.23,26.67 56.64,24.26 56.64,18.54 57.53,17.65 v57.53,16.13
  Bottom 0.203: v57.53,16.13 v51.56,16.13 45.72,16.13 44.45,14.86 v43.31,14.86
N$1
  Top 0.203: L.+ R1.2
N$2  (via drill 0.3 pad 0.64)
  Top 0.203: v15.24,23.5 14.35,23.5 R4.1
  Bottom 0.203: v15.24,23.5 15.24,25.78 14.48,26.54 14.48,41.66 11.17,44.96 J8.12
N$3
  Top 0.406: R13.2 PWR.+
N$4  (via drill 0.3 pad 0.64)
  Top 0.203: v11.43,27.3 13.08,27.3 13.46,26.92 R3.1 13.46,25.91
  Bottom 0.203: J8.10 11.73,31.57 11.73,27.61 v11.43,27.3
N$5
  Top 0.813: J3.+ 12.32,1.91 D4.+
N$6
  Top 0.406: TX.+ 2.73,26.04 3.11,26.42 6.22,26.42 R10.2
N$7
  Top 0.406: RX.+ R11.2
N$8
  Top 0.406: U3.7 17.14,44.32 R26.2
N$9
  Top 0.406: U3.2 23.5,44.07 23.11,44.45 R19.2
N$10
  Top 0.406: C4.2 18.03,46.35 18.54,45.85 R26.1 R19.1
N$11
  Top 0.813: F3.1 U8.2
N$12
  Top 0.203: U4.14 57.35,28.89 57.53,28.7 57.53,28.32 R16.1
N$13
  Top 0.406: R6.1 18.61,29.72 17.14,31.18 C15.1 R8.2
N$14
  Top 0.254: R2.2 22.73,30.48 24.26,30.48 R5.1
  Top 0.406: R2.2 21.91,29.72 20.38,31.24 C17.1
N$17
  Top 0.406: R12.2 RST.+
N$38
  Top 0.254: U1.1 35.57,8.39 R7.2
PB0
  Top 0.203: U2.12 30.21,33.42 28.7,34.92 28.7,46.17 30.41,47.88 38.73,47.88 PB.1
PB1/LED  (via drill 0.3 pad 0.64)
  Top 0.203: PB.2 36.58,48.26 30.21,48.26 28.32,46.37 28.32,34.54 30.25,32.62 U2.13 33,32.62 33.27,32.89 v34.29,32.89 | U4.3 48.29,31.47 v48.26,31.5
  Bottom 0.203: v48.26,31.5 36.96,31.5 35.56,32.89 v34.29,32.89
PB2/SS  (via drill 0.3 pad 0.64)
  Top 0.203: PB.3 34.42,48.64 30.01,48.64 27.94,46.57 27.94,34.29 30.41,31.82 U2.14 32.84,31.82 33.27,32.26 v33.66,32.26 | U4.4 49.19,30.82 v49.15,30.86
  Bottom 0.203: v49.15,30.86 36.32,30.86 34.92,32.26 v33.66,32.26
PB3/MOSI  (via drill 0.3 pad 0.64)
  Top 0.203: PB.4 32.26,49.02 29.82,49.02 27.56,46.76 27.56,33.91 30.45,31.02 U2.15 32.8,31.02 33.4,31.62 v34.29,31.62 | U4.5 48.32,30.17 v48.26,30.23
  Bottom 0.203: ICSP.5 64.77,29.21 64.77,31.62 64.52,31.88 62.48,31.88 62.23,31.62 62.23,30.48 61.98,30.23 v48.26,30.23 35.69,30.23 v34.29,31.62
PB4/MISO  (via drill 0.3 pad 0.64)
  Top 0.203: PB.5 30.1,49.4 29.6,49.4 27.18,46.98 27.18,33.66 30.61,30.22 U2.16 32.89,30.22 v33.66,30.99 | R16.2 61.72,27.56 62.23,28.07 62.23,29.21 ICSP.1
  Bottom 0.203: ICSP.1 62.61,29.59 35.05,29.59 v33.66,30.99
PB5/SCK  (via drill 0.3 pad 0.64)
  Top 0.203: PB.6 26.8,48.64 26.8,33.4 31.47,28.73 U2.17 32.54,28.73 v32.51,28.7 | v52.07,28.83 50.32,28.83 U4.7
  Bottom 0.203: ICSP.2 63.37,28.07 52.83,28.07 v52.07,28.83 51.82,29.08 32.89,29.08 v32.51,28.7
PC0
  Top 0.203: U2.23 38.2,27.96 41.64,24.51 51.79,24.51 53.59,22.71 53.59,5.33 PC.1
PC1
  Top 0.203: U2.24 38.99,27.73 41.83,24.89 52,24.89 53.98,22.92 53.98,3.17 PC.2
PC2
  Top 0.203: 40.39,30.1 40.51,30.22 | U2.25 40.51,30.22 | 40.51,30.22 40.51,30.23 42.67,30.23 43.05,29.84 43.05,26.29 44.07,25.27 52.2,25.27 54.36,23.12 54.36,4.06 PC.3
PC3
  Top 0.203: U2.26 42.89,31.02 43.43,30.48 43.43,26.42 44.2,25.65 52.4,25.65 54.74,23.32 54.74,4.95 55.88,3.81 57.15,3.81 PC.4
PC4/SDA  (via drill 0.3 pad 0.64)
  Top 0.203: U2.27 41.47,31.82 42.04,32.38 v43.05,32.38 43.81,31.62 43.81,26.67 44.45,26.04 52.65,26.04 55.12,23.57 55.12,5.21 56.13,4.19 59.31,4.19 PC.5
  Bottom 0.203: I2C.2 48.51,38.85 48.51,36.32 45.21,33.02 43.69,33.02 v43.05,32.38
PC5/SCL  (via drill 0.3 pad 0.64)
  Top 0.203: U2.28 41.51,32.62 41.91,33.02 43.69,33.02 v44.32,32.38 44.32,26.8 44.7,26.42 52.86,26.42 55.5,23.77 55.5,5.46 56.39,4.57 61.47,4.57 PC.6
  Bottom 0.203: v44.32,32.38 45.19,32.38 48.9,36.09 48.9,40.47 I2C.1
PD0/RX
  Top 0.203: U2.30 43.49,34.22 44.32,35.05 44.32,43.05 46.1,44.83 55.75,44.83 | 55.75,44.83 56.07,44.83 | 56.07,44.83 57.53,44.83 PD.1 | J6.3 59.23,42.37 UART.1 55.88,44.64 | 55.88,44.64 55.88,44.7 55.75,44.83 | 55.88,44.64 56.07,44.83
PD1/TX
  Top 0.203: U2.31 43.4,35.02 43.94,35.56 43.94,43.31 45.85,45.21 55.37,45.21 PD.2 | UART.2 58.69,40.37 J6.2
  Bottom 0.203: UART.2 55.99,40.37 57.28,41.66 57.28,47.12 PD.2
PD2/INT0  (via drill 0.3 pad 0.64)
  Top 0.203: PD.3 53.21,45.59 45.72,45.59 43.56,43.43 43.56,36.58 42.8,35.82 U2.32 39.38,35.82 39.12,35.56 v39.12,34.8
  Bottom 0.406: v39.12,34.8 PD2.2
PD3/INT1
  Top 0.203: U2.1 42.39,37.31 43.18,38.1 43.18,43.56 45.59,45.97 51.05,45.97 PD.4
PD4/SD_CS  (via drill 0.3 pad 0.64)
  Top 0.203: U2.2 38.2,38.07 38.48,38.35 42.04,38.35 42.8,39.12 42.8,43.81 45.34,46.35 48.9,46.35 PD.5 | v53.47,43.94 53.47,40.77 54.86,39.37 56.77,39.37 57.15,38.99 57.15,34.8 56.64,34.29 53.59,34.29 51.42,32.12 U4.2
  Bottom 0.203: v53.47,43.94 53.47,50.67 PD.5
PD5
  Top 0.203: U2.9 30.73,35.82 29.84,36.7 29.84,45.72 30.86,46.74 46.74,46.74 PD.6
PD6
  Top 0.203: U2.10 30.77,35.02 29.46,36.32 29.46,45.85 30.73,47.12 44.58,47.12 PD.7
PD7
  Top 0.203: U2.11 30.55,34.22 29.08,35.69 29.08,45.97 30.61,47.5 42.42,47.5 PD.8
PWR_IN  (via drill 0.38 pad 0.81)
  Top 0.813: 20.19,14.22 22.73,14.22 23.24,13.72 23.24,6.55 24.97,4.83 43.43,4.83 PR.1 | D1.- 20.13,14.35 C6.+ | 20.19,14.22 20.19,12.95 U8.1 | 20.19,14.22 C6.+ | D4.- v13.97,9.4 | v20.19,15.88 C6.+
  Bottom 0.813: v13.97,9.4 13.97,13.72 16.13,15.88 v20.19,15.88
RESET  (via drill 0.3 pad 0.64)
  Top 0.203: RST.- 1.14,20.7 1.6,20.25 9.45,20.25 11.05,21.84 12.57,21.84 R14.2 24,22.73 28.07,18.67 v28.07,17.91 | U2.29 44.43,33.42 45.09,32.77 v45.09,28.45 45.09,26.92 45.21,26.8 48.83,26.8 49.21,27.18 49.21,28.05 49.35,28.19 50.25,28.19 U4.8 51.79,28.22 v52.07,27.94 | PR.6 34.29,3.81 v39.37,3.81 | C5.1 64.26,32.13 64.77,31.62 64.77,26.67 ICSP.3
  Bottom 0.203: v28.07,17.91 28.07,17.27 24.77,13.97 RESET.P$2 26.29,1.65 32.13,1.65 PR.6 | v52.07,27.94 52.7,27.3 61.59,27.3 ICSP.3
  Bottom 0.254: v39.37,3.81 39.37,11.43 41.27,13.34 41.27,27.3 42.42,28.45 v45.09,28.45
RESET_W  (via drill 0.3 pad 0.64)
  Top 0.203: U1.59 35.97,22.89 36.58,23.5 v47.62,23.5 | U4.12 55.14,27.59 54.99,27.43 54.99,26.92 57.78,24.13 v57.78,23.5
  Bottom 0.203: v47.62,23.5 v57.78,23.5
RX+
  Top 0.203: J8.3 12.44,36.57 16.51,40.64 17.78,40.64 18.41,41.27 U3.6
RX-
  Top 0.203: U3.8 15.88,40.64 15.24,40.01 14.61,40.01 14.48,40.13 14.48,41.2 14.35,41.33 14.1,41.33 13.97,41.2 13.97,40.13 13.47,39.63 J8.6
RXIN  (via drill 0.3 pad 0.64)
  Top 0.203: U1.6 37.57,13.99 v36.96,14.61
  Top 0.406: U3.9 v15.88,32.38 15.62,32.13 R8.1
  Bottom 0.203: v36.96,14.61 37.21,14.86 37.21,15.11 22.86,29.46 17.91,29.46 16.89,30.48 16.89,30.86 16.76,30.99 16.41,30.99 16.28,31.11 16.28,31.37 16.41,31.5 16.76,31.5 16.89,31.62 16.89,32.13 16.64,32.38 v15.88,32.38
RXIP  (via drill 0.3 pad 0.64)
  Top 0.203: U1.5 37.17,13.25 v36.45,13.97
  Top 0.406: U3.11 v18.41,32.38 18.67,32.13 R6.2
  Bottom 0.203: v36.45,13.97 37.34,13.97 37.65,14.28 37.65,15.18 22.99,29.84 18.03,29.84 17.4,30.48 17.4,32.13 17.65,32.38 v18.41,32.38
RXLED  (via drill 0.3 pad 0.64)
  Top 0.203: U1.72 28.54,15.28 27.3,16.51 27.3,18.8 24.64,21.46 11.3,21.46 9.65,19.81 5.59,19.81 v5.33,19.56 | v4.83,23.62 1.91,23.62 RX.-
  Bottom 0.203: v5.33,19.56 5.33,23.11 v4.83,23.62
SCK  (via drill 0.3 pad 0.64)
  Top 0.203: v51.56,13.97 J1.5 | U4.13 54.91,28.23 54.61,27.94 54.61,26.8 57.02,24.38 57.02,18.8 58.17,17.65 v58.17,13.97 | U1.30 43.63,15.68 v43.56,15.75
  Bottom 0.203: v58.17,13.97 v51.56,13.97 43.18,13.97 42.67,14.48 42.67,15.11 43.31,15.75 v43.56,15.75
SD_CS  (via drill 0.3 pad 0.64)
  Top 0.203: U4.18 54.84,31.47 53.47,30.1 53.47,26.42 55.88,24 55.88,17.65 v56.26,17.27 | J1.2 v51.56,17.27 51.56,19.68 50.16,21.08 R17.2
  Top 0.254: J1.2
  Bottom 0.203: v56.26,17.27 v51.56,17.27
SEN
  Top 0.203: U1.31 47.19,16.07 47.5,16.38 47.5,17.14 R15.2 R17.1
SPDLED  (via drill 0.3 pad 0.64)
  Top 0.203: U1.67 30.1,17.27 24.13,23.24 16.64,23.24 v14.61,25.27
  Bottom 0.203: v14.61,25.27 14.1,25.78 14.1,41.02 12.45,42.67 12.44,42.67 J8.11
SS  (via drill 0.3 pad 0.64)
  Top 0.203: U1.29 46.64,15.28 v46.74,15.37 | U4.16 54.3,30.17 53.85,29.72 53.85,26.54 56.26,24.13 56.26,18.29 56.9,17.65 v56.9,15.37
  Bottom 0.203: v56.9,15.37 v46.74,15.37
TX+
  Top 0.203: J8.1 12.3,34.53 17.14,39.37 22.86,39.37 24.77,41.27 U3.1
TX-
  Top 0.203: J8.2 12.69,35.55 17.02,39.88 19.05,39.88 19.3,40.13 19.3,40.72 19.43,40.84 19.68,40.84 19.81,40.72 19.81,40.01 19.94,39.88 20.19,39.88 20.32,40.01 20.32,40.51 20.45,40.64 21.59,40.64 22.23,41.27 U3.3
TXLED  (via drill 0.3 pad 0.64)
  Top 0.203: U1.73 28.3,14.88 26.92,16.26 26.92,18.54 24.38,21.08 11.56,21.08 9.65,19.18 v6.22,19.18 | v4.83,25.27 1.91,25.27 TX.-
  Bottom 0.203: v6.22,19.18 6.22,23.88 v4.83,25.27
TXON  (via drill 0.3 pad 0.64)
  Top 0.203: U1.9 38.77,13.37 v39.37,13.97
  Top 0.406: U3.14 v22.23,32.38 21.97,32.13 R2.1
  Bottom 0.203: v39.37,13.97 38.48,13.97 38.1,14.35 38.1,15.24 23.24,30.1 23.24,31.62 22.48,32.38 v22.23,32.38
TXOP  (via drill 0.3 pad 0.64)
  Top 0.203: U1.8 38.37,14.24 v38.73,14.61
  Top 0.406: U3.16 v24.77,32.38 25.02,32.13 R5.2
  Bottom 0.203: v38.73,14.61 38.48,14.86 38.48,15.37 23.75,30.1 23.75,30.48 23.88,30.61 24.32,30.61 24.45,30.73 24.45,30.99 24.32,31.11 23.88,31.11 23.75,31.24 23.75,31.62 24.51,32.38 v24.77,32.38
VCC1V8
  Top 0.203: U1.7 37.97,8.25 | U1.7 37.97,9.02 38.1,9.02 | 38.1,9.02 39.37,9.02 39.57,9.22 U1.11 39.57,12.32 39.95,12.7 41.19,12.7 41.57,12.32 U1.16 41.57,9.27 41.44,9.14 41.3,9.14 41.17,9.27 U1.15 | C12.2 31.79,16.48 U1.69 35.18,16.48 35.56,16.09 35.56,15.49 | 38.1,9.02 37.97,9.14 | 38.1,9.02 37.97,8.89 | U1.74 35.18,14.47 35.56,14.86 35.56,15.24 | 35.56,15.24 35.56,15.49 | 37.97,15.24 U1.7 | 37.97,15.24 37.85,15.37 | 37.97,15.24 37.98,15.24 38.1,15.37 | 38.1,15.37 35.69,15.37 | 35.69,15.37 35.56,15.49 | 35.69,15.37 35.56,15.24 | 38.1,15.37 40.51,15.37 42.02,16.88 U1.33
  Top 0.254: 37.97,8.25 C10.2
XTAL1
  Top 0.406: X4.2 34.67,41.02 C22.2 34.2,39.27 U2.7
XTAL2
  Top 0.406: U2.8 33.4,39.38 C23.2 33.02,40.89 X4.1
XTLN
  Top 0.203: X2.1 28.83,12.32 C16.1 30.23,12.19 R9.2 32,12.57 32,13.59 32.49,14.07 U1.75
XTLP
  Top 0.203: X2.2 28.83,10.54 C9.2 30.23,10.67 R9.1 31.75,10.67 32.51,11.43 32.51,13.46 32.73,13.68 U1.76

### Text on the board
tPlace: AREF | GND | 13 | 12 | 11 | 10 | 9 | 8 | 7 | 6 | 5 | 4 | 3 | 2 | 1 | 0 | GND | DIGITAL | GND | 5V | SCL | RX | SDA | TX | RX | 5V | 5V | GND | GND | TX | DTR | ANALOG IN | RST | 3V3 | 5V | GND | GND | VIN | 0 | 1 | 2 | 3 | 4 | 5
bPlace: Seeeduino Ethernet | v0.9b by Seeed Studio 04/28/2012 | www.seeedstudio.com | INT | MISO | 5V | SCK | MOSI | RST | GND | 9V DC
